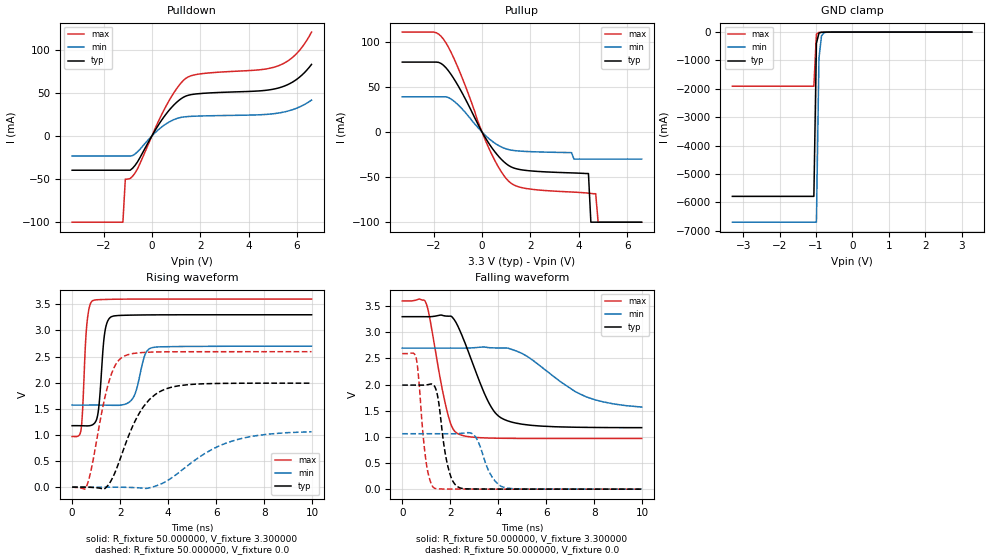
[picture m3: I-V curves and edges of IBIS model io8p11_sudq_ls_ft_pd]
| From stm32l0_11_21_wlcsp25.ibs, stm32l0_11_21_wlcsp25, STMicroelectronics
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|   Model io8p11_sudq_ls_ft_pd
[Model]  io8p11_sudq_ls_ft_pd
Model_type I/O
Polarity   Non-Inverting
Enable   Active-Low
Vinl =   0.990000V
Vinh =   2.310000V
Vmeas =  1.650000V
Cref =   50.000000pF
Rref =   100.000000M
Vref =   0.0V
C_comp   2.343000pF   2.309800pF   2.393900pF
[Temperature Range]   25.000000   0.125000k   -40.000000
[Pullup Reference]   3.300000V   2.700000V   3.600000V
[Pulldown Reference]   0.0V   0.0V   0.0V
[POWER Clamp Reference]   3.300000V   2.700000V   3.600000V
[GND Clamp Reference]   0.0V   0.0V   0.0V
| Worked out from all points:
|   slope of the pulldown table from 0 to 0.495 V, typ, clamps not added: 22.6 ohm
|   slope of the pullup table from 0 to 0.495 V, typ, clamps not added: 23.9 ohm
|   GND clamp passes 1 mA (typ) near -0.64 V on its own axis
|   rising waveform, R_fixture 50.000000, V_fixture 3.300000: 20-80 % time 209ps typ, 361ps min, 167ps max; typ from 1.18 V to 3.3 V
|   rising waveform, R_fixture 50.000000, V_fixture 0.0: 20-80 % time 1.18ns typ, 2.2ns min, 697ps max; typ from 0 V to 1.99 V
|   falling waveform, R_fixture 50.000000, V_fixture 3.300000: 20-80 % time 1.12ns typ, 2.1ns min, 643ps max; typ from 3.3 V to 1.18 V
|   falling waveform, R_fixture 50.000000, V_fixture 0.0: 20-80 % time 383ps typ, 557ps min, 303ps max; typ from 1.99 V to 0 V
[Pulldown]
|Voltage   I(typ)   I(min)   I(max)
-3.3V     -39.8mA    -23.38mA   -100mA
-1.2V     -39.8mA    -23.38mA   -100mA
-1.1V     -39.8mA    -23.38mA   -50.11mA
-900mV    -39.8mA    -23.38mA   -49.43mA
-700mV    -34.25mA   -21mA      -43.13mA
600mV     25.84mA    14.18mA    35.34mA
1V        38.32mA    19.82mA    53.81mA
1.4V      46.09mA    22.19mA    66.63mA
2V        49.05mA    23.02mA    71.83mA
5.2V      55.23mA    26.32mA    80.92mA
6V        65.76mA    32.26mA    95.84mA
6.6V      82.81mA    41.44mA    120.2mA
[Pullup]
|Voltage   I(typ)   I(min)   I(max)
-3.3V     77.64mA    39.16mA    110.9mA
-2V       77.64mA    39.16mA    110.9mA
-1.6V     74.23mA    39.16mA    103.2mA
-900mV    47.14mA    27.82mA    65.37mA
300mV     -13.29mA   -7.65mA    -18.99mA
1.2V      -38.62mA   -20mA      -56.79mA
3.7V      -45.29mA   -22.8mA    -66.51mA
4.4V      -46mA      -30mA      -67.77mA
4.5V      -100mA     -30mA      -68.06mA
4.7V      -100mA     -30mA      -68.41mA
4.8V      -100mA     -30mA      -100mA
6.6V      -100mA     -30mA      -100mA
[GND_clamp]
|Voltage   I(typ)   I(min)   I(max)
-3.3V     -5.787A    -6.696A    -1.906A
-1.06V    -5.787A    -6.696A    -1.906A
-990mV    -393.4mA   -6.696A    -70.76mA
-920mV    -33.04mA   -919.4mA   -10.91mA
-850mV    -6.842mA   -131.3mA   -6.529mA
-780mV    -3.49mA    -21.08mA   -4.216mA
3.28V     73.94uA    88.61uA    51.47uA
[POWER_clamp]
|Voltage   I(typ)   I(min)   I(max)
-3.28V    0A         0A         0A
0V        0A         0A         0A
[Ramp]
| variable   typ   min   max
dV/dt_r  1.19376/1.17474n   0.61074/2.08381n   1.55514/0.69552n
dV/dt_f  1.27188/1.12023n   0.59316/1.87550n   1.57763/0.64183n
R_load = 50.000000
[Rising Waveform]
R_fixture= 50.000000
V_fixture= 3.300000
V_fixture_min= 2.700000
V_fixture_max= 3.600000
|time   V(typ)   V(min)   V(max)
0s        1.176V     1.571V     968.9mV
380.4ps   1.175V     1.571V     1.128V
600.6ps   1.173V     1.571V     3.05V
860.9ps   1.196V     1.571V     3.57V
1.101ns   1.493V     1.571V     3.588V
1.381ns   3.018V     1.569V     3.592V
1.642ns   3.263V     1.567V     3.595V
2.523ns   3.292V     1.697V     3.599V
3.283ns   3.297V     2.662V     3.599V
9.97ns    3.299V     2.698V     3.599V
[Rising Waveform]
R_fixture= 50.000000
V_fixture= 0.0
V_fixture_min= 0.0
V_fixture_max= 0.0
|time   V(typ)   V(min)   V(max)
0s        -3.216uV   7.827uV    -231.3uV
620.6ps   -747.1uV   -8.106uV   39.59mV
820.8ps   -5.23mV    3.784uV    394.6mV
1.502ns   39.33mV    181.2uV    1.968V
1.802ns   299.1mV    -186.8uV   2.336V
2.122ns   696.8mV    -2.275mV   2.496V
2.983ns   1.547V     -22.83mV   2.578V
3.944ns   1.886V     117.8mV    2.59V
6.466ns   1.986V     851.5mV    2.592V
9.97ns    1.99V      1.06V      2.592V
[Falling Waveform]
R_fixture= 50.000000
V_fixture= 3.300000
V_fixture_min= 2.700000
V_fixture_max= 3.600000
|time   V(typ)   V(min)   V(max)
0s        3.299V     2.698V     3.599V
1.001ns   3.298V     2.698V     3.545V
1.842ns   3.31V      2.698V     1.54V
2.062ns   3.298V     2.698V     1.2V
2.302ns   3.13V      2.698V     1.064V
3.504ns   1.747V     2.713V     979.4mV
4.124ns   1.361V     2.7V       973.3mV
5.205ns   1.23V      2.54V      970.1mV
7.648ns   1.182V     1.767V     969mV
9.97ns    1.176V     1.571V     968.9mV
[Falling Waveform]
R_fixture= 50.000000
V_fixture= 0.0
V_fixture_min= 0.0
V_fixture_max= 0.0
|time   V(typ)   V(min)   V(max)
0s        1.99V      1.06V      2.592V
580.6ps   1.99V      1.06V      2.505V
981ps     1.993V     1.06V      565.7mV
1.341ns   1.972V     1.06V      19.6mV
1.902ns   432mV      1.06V      2.299mV
2.382ns   28.37mV    1.064V     1.461mV
3.043ns   2.853mV    1.006V     663uV
3.664ns   1.834mV    293.4mV    216.5uV
4.264ns   1.226mV    30.55mV    -9.331uV
9.97ns    -3.216uV   7.827uV    -231.3uV
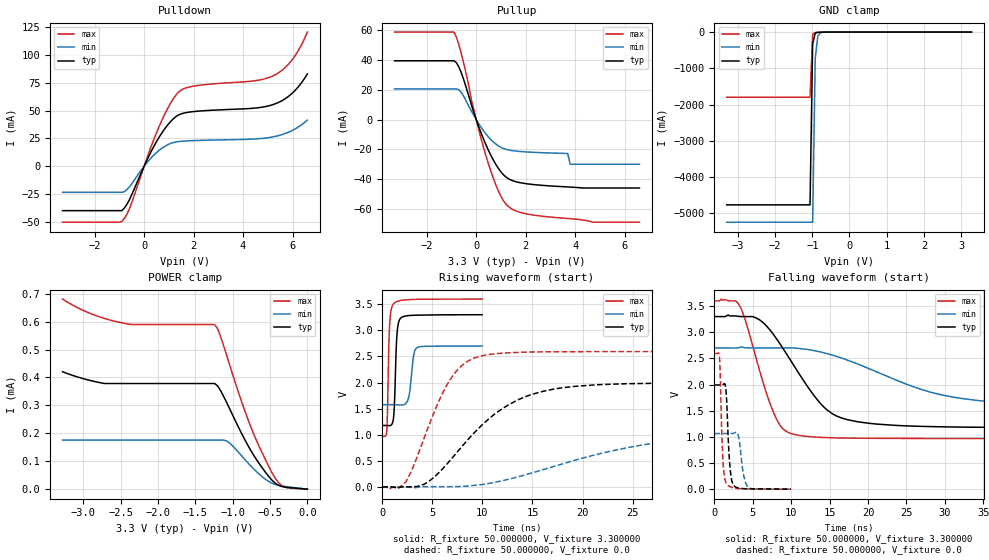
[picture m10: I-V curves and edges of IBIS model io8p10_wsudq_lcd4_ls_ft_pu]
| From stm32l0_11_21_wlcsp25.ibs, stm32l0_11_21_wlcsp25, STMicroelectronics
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|   Model io8p10_wsudq_lcd4_ls_ft_pu
[Model]  io8p10_wsudq_lcd4_ls_ft_pu
Model_type I/O
Polarity   Non-Inverting
Enable   Active-Low
Vinl =   0.990000V
Vinh =   2.310000V
Vmeas =  1.650000V
Cref =   50.000000pF
Rref =   100.000000M
Vref =   0.0V
C_comp   3.263700pF   3.224800pF   3.309000pF
[Temperature Range]   25.000000   0.125000k   -40.000000
[Pullup Reference]   3.300000V   2.700000V   3.600000V
[Pulldown Reference]   0.0V   0.0V   0.0V
[POWER Clamp Reference]   3.300000V   2.700000V   3.600000V
[GND Clamp Reference]   0.0V   0.0V   0.0V
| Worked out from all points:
|   slope of the pulldown table from 0 to 0.495 V, typ, clamps not added: 22.6 ohm
|   slope of the pullup table from 0 to 0.495 V, typ, clamps not added: 23.9 ohm
|   GND clamp passes 1 mA (typ) near -0.64 V on its own axis
|   rising waveform, R_fixture 50.000000, V_fixture 3.300000: 20-80 % time 236ps typ, 375ps min, 200ps max; typ from 1.18 V to 3.3 V
|   rising waveform, R_fixture 50.000000, V_fixture 0.0: 20-80 % time 6.54ns typ, 13.7ns min, 3.48ns max; typ from 0.001 V to 1.99 V
|   falling waveform, R_fixture 50.000000, V_fixture 3.300000: 20-80 % time 5.96ns typ, 12.5ns min, 3.27ns max; typ from 3.3 V to 1.18 V
|   falling waveform, R_fixture 50.000000, V_fixture 0.0: 20-80 % time 420ps typ, 583ps min, 344ps max; typ from 1.99 V to 0.001 V
[Pulldown]
|Voltage   I(typ)   I(min)   I(max)
-3.3V     -39.83mA   -23.37mA   -50.2mA
-900mV    -39.83mA   -23.37mA   -49.52mA
-600mV    -30.28mA   -18.59mA   -38.45mA
100mV     4.867mA    2.821mA    6.48mA
600mV     25.85mA    14.17mA    35.39mA
1V        38.33mA    19.81mA    53.88mA
1.4V      46.1mA     22.18mA    66.72mA
2V        49.07mA    23.02mA    71.93mA
4.4V      52.05mA    24.38mA    76.53mA
5.2V      55.25mA    26.31mA    81.02mA
6V        65.78mA    32.24mA    95.96mA
6.6V      82.83mA    41.41mA    120.4mA
[Pullup]
|Voltage   I(typ)   I(min)   I(max)
-3.3V     39.53mA    20.64mA    58.82mA
-900mV    39.53mA    20.64mA    58.82mA
-600mV    31.26mA    18.2mA     44.19mA
0V        90fA       25.2pA     100fA
500mV     -20.88mA   -11.78mA   -30.07mA
900mV     -32.92mA   -17.72mA   -48.14mA
1.3V      -39.75mA   -20.41mA   -58.47mA
2V        -43.05mA   -21.73mA   -63.29mA
3.7V      -45.29mA   -22.8mA    -66.51mA
3.8V      -45.39mA   -30mA      -66.64mA
4.7V      -46.01mA   -30mA      -69mA
6.6V      -46.01mA   -30mA      -69mA
[GND_clamp]
|Voltage   I(typ)   I(min)   I(max)
-3.3V     -4.767A    -5.245A    -1.798A
-1.06V    -4.767A    -5.245A    -1.798A
-990mV    -327.3mA   -5.245A    -68.38mA
-920mV    -29.22mA   -722.7mA   -11.24mA
-850mV    -6.771mA   -104.4mA   -6.721mA
-780mV    -3.56mA    -17.38mA   -4.326mA
-500mV    -59.41uA   -172uA     -34.91uA
3.28V     0A         0A         0A
[POWER_clamp]
|Voltage   I(typ)   I(min)   I(max)
-3.28V    420.5uA    175.8uA    680.7uA
-2.72V    378.4uA    175.8uA    611.5uA
-2.4V     378.3uA    175.8uA    591.3uA
-1.24V    378.3uA    175.8uA    588.9uA
-1.2V     368.9uA    175.8uA    573.6uA
-1.08V    309.6uA    172.2uA    478.3uA
-920mV    220.5uA    131.5uA    344.5uA
-760mV    139.7uA    83.77uA    224.7uA
-480mV    33.95uA    22.2uA     61.82uA
-400mV    15.86uA    14.75uA    27.74uA
-320mV    8.148uA    10.83uA    9.341uA
0V        0A         0A         0A
[Ramp]
| variable   typ   min   max
dV/dt_r  1.19492/6.52951n   0.62963/13.59700n   1.55547/3.47803n
dV/dt_f  1.27308/5.95302n   0.65238/12.42018n   1.57816/3.26943n
R_load = 50.000000
[Rising Waveform]
R_fixture= 50.000000
V_fixture= 3.300000
V_fixture_min= 2.700000
V_fixture_max= 3.600000
|time   V(typ)   V(min)   V(max)
0s        1.178V     1.575V     969.7mV
440.4ps   1.177V     1.575V     1.077V
720.7ps   1.174V     1.575V     3.085V
1.081ns   1.277V     1.576V     3.5V
1.201ns   1.569V     1.576V     3.525V
1.461ns   2.924V     1.574V     3.553V
1.822ns   3.233V     1.57V      3.573V
2.583ns   3.282V     1.686V     3.587V
3.423ns   3.291V     2.663V     3.595V
9.97ns    3.3V       2.7V       3.6V
[Rising Waveform]
R_fixture= 50.000000
V_fixture= 0.0
V_fixture_min= 0.0
V_fixture_max= 0.0
|time   V(typ)   V(min)   V(max)
0s        1.062mV    1.811mV    1.012mV
2.302ns   1.368mV    197.1uV    88.03mV
4.204ns   54.26mV    3.505mV    951.3mV
6.507ns   450.1mV    3.887mV    1.972V
8.008ns   787.3mV    9.915mV    2.337V
9.51ns    1.102V     35.62mV    2.49V
13.61ns   1.674V     196.3mV    2.579V
18.42ns   1.909V     465.1mV    2.591V
30.83ns   1.99V      925.8mV    2.593V
49.85ns   1.993V     1.064V     2.593V
[Falling Waveform]
R_fixture= 50.000000
V_fixture= 3.300000
V_fixture_min= 2.700000
V_fixture_max= 3.600000
|time   V(typ)   V(min)   V(max)
0s        3.3V       2.7V       3.6V
3.303ns   3.302V     2.711V     3.5V
5.606ns   3.26V      2.702V     2.41V
7.508ns   2.992V     2.702V     1.536V
8.609ns   2.762V     2.701V     1.207V
9.91ns    2.465V     2.701V     1.068V
13.91ns   1.622V     2.621V     991.1mV
17.32ns   1.329V     2.468V     977.4mV
30.03ns   1.192V     1.79V      970mV
49.85ns   1.178V     1.575V     969.7mV
[Falling Waveform]
R_fixture= 50.000000
V_fixture= 0.0
V_fixture_min= 0.0
V_fixture_max= 0.0
|time   V(typ)   V(min)   V(max)
0s        1.993V     1.064V     2.593V
640.6ps   1.993V     1.064V     2.54V
1.101ns   1.998V     1.064V     559.8mV
1.562ns   1.769V     1.064V     107.5mV
2.002ns   463.7mV    1.064V     51.1mV
2.482ns   78.53mV    1.069V     25.83mV
3.143ns   22.38mV    1.004V     12.57mV
3.824ns   11.22mV    255.2mV    8.965mV
4.384ns   8.123mV    36.5mV     5.504mV
9.97ns    1.062mV    1.811mV    1.012mV
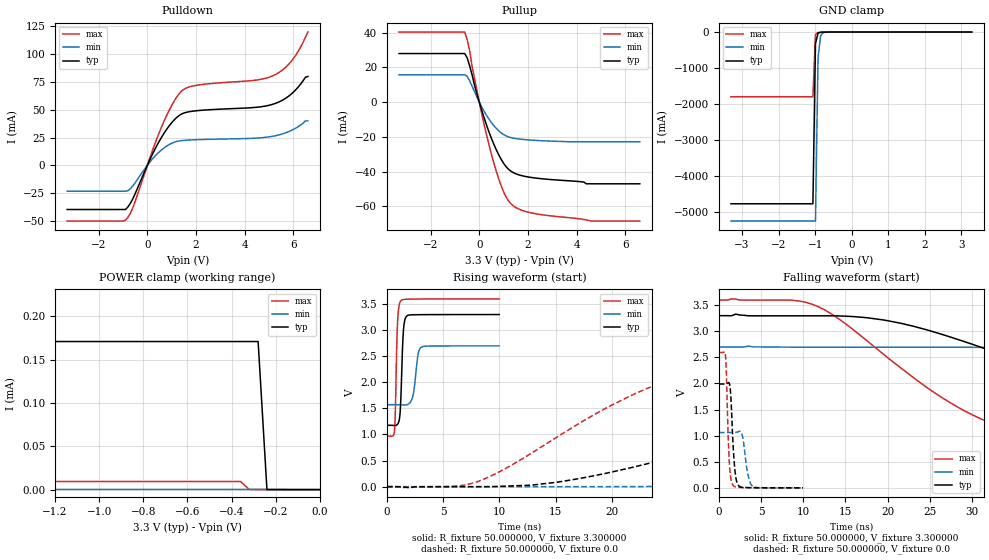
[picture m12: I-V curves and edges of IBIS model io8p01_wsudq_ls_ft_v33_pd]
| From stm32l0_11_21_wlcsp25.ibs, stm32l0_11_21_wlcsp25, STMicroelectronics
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|   Model io8p01_wsudq_ls_ft_v33_pd
[Model]  io8p01_wsudq_ls_ft_v33_pd
Model_type I/O
Polarity   Non-Inverting
Enable   Active-Low
Vinl =   0.990000V
Vinh =   2.310000V
Vmeas =  1.650000V
Cref =   50.000000pF
Rref =   100.000000M
Vref =   0.0V
C_comp   2.653200pF   2.620200pF   2.695100pF
[Temperature Range]   25.000000   0.125000k   -40.000000
[Pullup Reference]   3.300000V   2.700000V   3.600000V
[Pulldown Reference]   0.0V   0.0V   0.0V
[POWER Clamp Reference]   3.300000V   2.700000V   3.600000V
[GND Clamp Reference]   0.0V   0.0V   0.0V
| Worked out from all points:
|   slope of the pulldown table from 0 to 0.495 V, typ, clamps not added: 22.6 ohm
|   slope of the pullup table from 0 to 0.495 V, typ, clamps not added: 23.9 ohm
|   GND clamp passes 1 mA (typ) near -0.64 V on its own axis
|   POWER clamp passes 1 mA (typ) near -2.99 V on its own axis
|   rising waveform, R_fixture 50.000000, V_fixture 3.300000: 20-80 % time 213ps typ, 362ps min, 177ps max; typ from 1.18 V to 3.3 V
|   rising waveform, R_fixture 50.000000, V_fixture 0.0: 20-80 % time 27ns typ, 59.9ns min, 13.6ns max; typ from 0 V to 1.99 V
|   falling waveform, R_fixture 50.000000, V_fixture 3.300000: 20-80 % time 24.2ns typ, 53.6ns min, 13.3ns max; typ from 3.3 V to 1.18 V
|   falling waveform, R_fixture 50.000000, V_fixture 0.0: 20-80 % time 397ps typ, 564ps min, 318ps max; typ from 1.99 V to 0 V
[Pulldown]
|Voltage   I(typ)   I(min)   I(max)
-3.3V     -39.83mA   -23.37mA   -50.2mA
-900mV    -39.83mA   -23.37mA   -49.53mA
-600mV    -30.28mA   -18.59mA   -38.45mA
500mV     22.11mA    12.28mA    30.1mA
1V        38.33mA    19.81mA    53.88mA
1.4V      46.1mA     22.18mA    66.72mA
2V        49.07mA    23.01mA    71.93mA
4.4V      52.05mA    24.38mA    76.53mA
5.2V      55.25mA    26.3mA     81.02mA
5.9V      63.83mA    31.17mA    93.18mA
6.2V      70.39mA    34.75mA    102.6mA
6.6V      80mA       40mA       120mA
[Pullup]
|Voltage   I(typ)   I(min)   I(max)
-3.3V     27.93mA    15.71mA    40.32mA
-600mV    27.93mA    15.71mA    40.32mA
-400mV    21.1mA     12.32mA    29.91mA
-300mV    15.89mA    9.293mA    20.96mA
200mV     -9.114mA   -5.293mA   -12.98mA
600mV     -24.28mA   -13.56mA   -35.12mA
1V        -35.19mA   -18.68mA   -51.62mA
1.2V      -38.61mA   -19.99mA   -56.78mA
1.4V      -40.59mA   -20.71mA   -59.71mA
2.2V      -43.48mA   -21.92mA   -63.91mA
4.6V      -47mA      -22.8mA    -68.41mA
6.6V      -47mA      -22.8mA    -68.41mA
[GND_clamp]
|Voltage   I(typ)   I(min)   I(max)
-3.3V     -4.766A    -5.244A    -1.797A
-1.06V    -4.766A    -5.244A    -1.797A
-990mV    -326.8mA   -5.244A    -68.06mA
-920mV    -29.1mA    -722.2mA   -11.17mA
-850mV    -6.81mA    -104.4mA   -6.691mA
-780mV    -3.567mA   -17.46mA   -4.273mA
-500mV    -68.7uA    -184.5uA   -41.56uA
3.28V     73.95uA    88.62uA    51.48uA
[POWER_clamp]
|Voltage   I(typ)   I(min)   I(max)
-3.28V    3.05A      15.65uA    3.723A
-3.2V     3.05A      1.687uA    3.723A
-2.96V    269.4uA    209.1nA    3.723A
-2.92V    170.9uA    209.1nA    508.5mA
-2.8V     170.9uA    209.1nA    1.296mA
-2.76V    170.9uA    209.1nA    177.1uA
-2.72V    170.9uA    209.1nA    24.25uA
-2.68V    170.9uA    209.1nA    9.362uA
-360mV    170.9uA    209.1nA    9.362uA
-280mV    170.9uA    209.1nA    0A
-240mV    0A         209.1nA    0A
0V        0A         0A         0A
[Ramp]
| variable   typ   min   max
dV/dt_r  1.19406/26.98015n   0.63468/59.90792n   1.55520/13.55529n
dV/dt_f  1.27386/24.20488n   0.67110/53.55729n   1.57835/13.29450n
R_load = 50.000000
[Rising Waveform]
R_fixture= 50.000000
V_fixture= 3.300000
V_fixture_min= 2.700000
V_fixture_max= 3.600000
|time   V(typ)   V(min)   V(max)
0s        1.176V     1.571V     968.9mV
660.7ps   1.172V     1.571V     1.057V
940.9ps   1.196V     1.571V     3.149V
1.221ns   1.638V     1.569V     3.56V
1.441ns   2.929V     1.566V     3.586V
1.742ns   3.267V     1.568V     3.592V
2.302ns   3.294V     1.738V     3.595V
2.743ns   3.296V     2.509V     3.596V
3.083ns   3.297V     2.678V     3.597V
9.97ns    3.299V     2.698V     3.599V
[Rising Waveform]
R_fixture= 50.000000
V_fixture= 0.0
V_fixture_min= 0.0
V_fixture_max= 0.0
|time   V(typ)   V(min)   V(max)
0s        2.232nV    16.52nV    4.706nV
8.008ns   -306uV     -170.1uV   93.09mV
15.02ns   82.63mV    -141.4uV   937.3mV
24.02ns   485.9mV    3.356mV    1.96V
29.53ns   789.1mV    20.61mV    2.309V
37.04ns   1.162V     62.98mV    2.5V
55.06ns   1.717V     255.6mV    2.581V
78.58ns   1.935V     558.3mV    2.591V
146.1ns   1.99V      988.5mV    2.592V
249.2ns   1.99V      1.06V      2.592V
[Falling Waveform]
R_fixture= 50.000000
V_fixture= 3.300000
V_fixture_min= 2.700000
V_fixture_max= 3.600000
|time   V(typ)   V(min)   V(max)
0s        3.299V     2.698V     3.599V
11.51ns   3.296V     2.695V     3.489V
19.52ns   3.217V     2.695V     2.558V
28.53ns   2.832V     2.695V     1.527V
33.03ns   2.586V     2.687V     1.202V
38.04ns   2.302V     2.668V     1.07V
55.56ns   1.482V     2.518V     987.8mV
75.58ns   1.262V     2.244V     973.4mV
131.6ns   1.183V     1.701V     969.1mV
249.2ns   1.176V     1.571V     968.9mV
[Falling Waveform]
R_fixture= 50.000000
V_fixture= 0.0
V_fixture_min= 0.0
V_fixture_max= 0.0
|time   V(typ)   V(min)   V(max)
0s        1.99V      1.06V      2.592V
780.8ps   1.989V     1.06V      2.533V
1.221ns   2.006V     1.06V      527mV
1.421ns   1.731V     1.06V      174.8mV
1.642ns   939.5mV    1.06V      57.09mV
1.982ns   224.5mV    1.061V     17.01mV
2.462ns   25.32mV    1.085V     8.238mV
2.783ns   9.519mV    995.9mV    5.928mV
3.924ns   3.223mV    41.26mV    1.619mV
9.97ns    2.232nV    16.52nV    4.706nV
